VERSION 5.6 ;
BUSBITCHARS "[]" ;
DIVIDERCHAR "/" ;

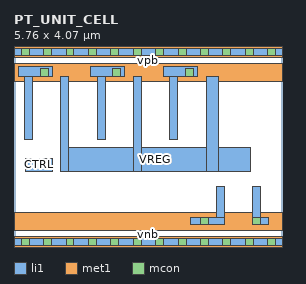
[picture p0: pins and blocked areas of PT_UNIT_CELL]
MACRO PT_UNIT_CELL
  CLASS CORE ;
  ORIGIN 0 0 ;
  FOREIGN PT_UNIT_CELL 0 0 ;
  SIZE 5.76 BY 4.07 ;
  SYMMETRY X Y ;
  SITE unithd ;
  PIN CTRL
    DIRECTION INPUT ;
    USE SIGNAL ;
    PORT
      LAYER li1 ;
        RECT 0.245 1.515 0.82 1.785 ;
    END
  END CTRL
  PIN VREG
    DIRECTION INOUT ;
    USE POWER ;
    PORT
      LAYER li1 ;
        RECT 1 1.51 5.06 2.02 ;
        RECT 4.12 1.51 4.37 3.54 ;
        RECT 2.56 1.51 2.73 3.54 ;
        RECT 1 1.51 1.17 3.54 ;
    END
  END VREG
  PIN vgnd
    DIRECTION INOUT ;
    USE GROUND ;
    PORT
      LAYER met1 ;
        RECT 0 0.255 5.76 0.625 ;
      LAYER li1 ;
        RECT 5.115 0.365 5.455 0.535 ;
        RECT 5.115 0.365 5.285 1.185 ;
        RECT 4.335 0.365 4.505 1.185 ;
        RECT 3.78 0.365 4.505 0.535 ;
      LAYER mcon ;
        RECT 3.995 0.365 4.165 0.535 ;
        RECT 5.115 0.365 5.285 0.535 ;
    END
  END vgnd
  PIN vnb
    DIRECTION INOUT ;
    USE GROUND ;
    PORT
      LAYER met1 ;
        RECT 0 -0.115 5.76 0.115 ;
      LAYER li1 ;
        RECT 0 -0.085 5.76 0.085 ;
      LAYER mcon ;
        RECT 0.155 -0.085 0.325 0.085 ;
        RECT 0.635 -0.085 0.805 0.085 ;
        RECT 1.115 -0.085 1.285 0.085 ;
        RECT 1.595 -0.085 1.765 0.085 ;
        RECT 2.075 -0.085 2.245 0.085 ;
        RECT 2.555 -0.085 2.725 0.085 ;
        RECT 3.035 -0.085 3.205 0.085 ;
        RECT 3.515 -0.085 3.685 0.085 ;
        RECT 3.995 -0.085 4.165 0.085 ;
        RECT 4.475 -0.085 4.645 0.085 ;
        RECT 4.955 -0.085 5.125 0.085 ;
        RECT 5.435 -0.085 5.605 0.085 ;
    END
  END vnb
  PIN vpb
    DIRECTION INOUT ;
    USE POWER ;
    PORT
      LAYER met1 ;
        RECT 0 3.955 5.76 4.185 ;
      LAYER li1 ;
        RECT 0 3.985 5.76 4.155 ;
      LAYER mcon ;
        RECT 0.155 3.985 0.325 4.155 ;
        RECT 0.635 3.985 0.805 4.155 ;
        RECT 1.115 3.985 1.285 4.155 ;
        RECT 1.595 3.985 1.765 4.155 ;
        RECT 2.075 3.985 2.245 4.155 ;
        RECT 2.555 3.985 2.725 4.155 ;
        RECT 3.035 3.985 3.205 4.155 ;
        RECT 3.515 3.985 3.685 4.155 ;
        RECT 3.995 3.985 4.165 4.155 ;
        RECT 4.475 3.985 4.645 4.155 ;
        RECT 4.955 3.985 5.125 4.155 ;
        RECT 5.435 3.985 5.605 4.155 ;
    END
  END vpb
  PIN vpwr
    DIRECTION INOUT ;
    USE POWER ;
    PORT
      LAYER met1 ;
        RECT 0 3.445 5.76 3.815 ;
      LAYER li1 ;
        RECT 3.205 3.54 3.93 3.755 ;
        RECT 3.34 2.19 3.51 3.755 ;
        RECT 1.645 3.54 2.37 3.755 ;
        RECT 1.78 2.19 1.95 3.755 ;
        RECT 0.09 3.54 0.815 3.755 ;
        RECT 0.22 2.19 0.39 3.755 ;
      LAYER mcon ;
        RECT 0.565 3.54 0.735 3.71 ;
        RECT 2.12 3.54 2.29 3.71 ;
        RECT 3.68 3.54 3.85 3.71 ;
    END
  END vpwr
END PT_UNIT_CELL

END LIBRARY
